VERSION 5.8 ;
BUSBITCHARS "[]" ;
DIVIDERCHAR "/" ;
UNITS
    DATABASE MICRONS 1000 ;
END UNITS

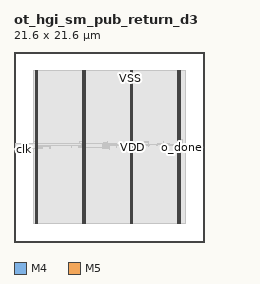
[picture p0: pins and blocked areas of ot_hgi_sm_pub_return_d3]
MACRO ot_hgi_sm_pub_return_d3
  FOREIGN ot_hgi_sm_pub_return_d3 0 0 ;
  CLASS BLOCK ;
  SIZE 21.6 BY 21.6 ;
  PIN clk
    DIRECTION INPUT ;
    USE SIGNAL ;
    PORT
      LAYER M4 ;
        RECT  0 10.512 0.084 10.536 ;
    END
  END clk
  PIN i_done
    DIRECTION INPUT ;
    USE SIGNAL ;
    PORT
      LAYER M4 ;
        RECT  0 10.608 0.084 10.632 ;
    END
  END i_done
  PIN i_fault
    DIRECTION INPUT ;
    USE SIGNAL ;
    PORT
      LAYER M4 ;
        RECT  0 10.704 0.084 10.728 ;
    END
  END i_fault
  PIN o_done
    DIRECTION OUTPUT ;
    USE SIGNAL ;
    PORT
      LAYER M4 ;
        RECT  21.516 10.704 21.6 10.728 ;
    END
  END o_done
  PIN o_fault
    DIRECTION OUTPUT ;
    USE SIGNAL ;
    PORT
      LAYER M4 ;
        RECT  21.516 10.8 21.6 10.824 ;
    END
  END o_fault
  PIN rn
    DIRECTION INPUT ;
    USE SIGNAL ;
    PORT
      LAYER M4 ;
        RECT  0 10.8 0.084 10.824 ;
    END
  END rn
  PIN VDD
    DIRECTION INOUT ;
    USE POWER ;
    PORT
      LAYER M5 ;
        RECT  18.792 2.151 18.912 19.449 ;
        RECT  13.392 2.151 13.512 19.449 ;
        RECT  7.992 2.151 8.112 19.449 ;
        RECT  2.592 2.151 2.712 19.449 ;
    END
  END VDD
  PIN VSS
    DIRECTION INOUT ;
    USE GROUND ;
    PORT
      LAYER M5 ;
        RECT  18.6 2.137 18.72 19.463 ;
        RECT  13.2 2.137 13.32 19.463 ;
        RECT  7.8 2.137 7.92 19.463 ;
        RECT  2.4 2.137 2.52 19.463 ;
    END
  END VSS
  # OT_OBS_CLOSED layer=M5 d_um=1.536 added=0
  OBS
    LAYER RVTN ;
     RECT  2.16 2.16 19.44 2.295 ;
     RECT  2.16 2.565 19.44 2.835 ;
     RECT  2.16 3.105 19.44 3.375 ;
     RECT  2.16 3.645 19.44 3.915 ;
     RECT  2.16 4.185 19.44 4.455 ;
     RECT  2.16 4.725 19.44 4.995 ;
     RECT  2.16 5.265 19.44 5.535 ;
     RECT  2.16 5.805 19.44 6.075 ;
     RECT  2.16 6.345 19.44 6.615 ;
     RECT  2.16 6.885 19.44 7.155 ;
     RECT  2.16 7.425 19.44 7.695 ;
     RECT  2.16 7.965 19.44 8.235 ;
     RECT  2.16 8.505 19.44 8.775 ;
     RECT  2.16 9.045 19.44 9.315 ;
     RECT  2.16 9.585 19.44 9.855 ;
     RECT  2.16 10.125 19.44 10.395 ;
     RECT  2.16 10.665 19.44 10.935 ;
     RECT  2.16 11.205 19.44 11.475 ;
     RECT  2.16 11.745 19.44 12.015 ;
     RECT  2.16 12.285 19.44 12.555 ;
     RECT  2.16 12.825 19.44 13.095 ;
     RECT  2.16 13.365 19.44 13.635 ;
     RECT  2.16 13.905 19.44 14.175 ;
     RECT  2.16 14.445 19.44 14.715 ;
     RECT  2.16 14.985 19.44 15.255 ;
     RECT  2.16 15.525 19.44 15.795 ;
     RECT  2.16 16.065 19.44 16.335 ;
     RECT  2.16 16.605 19.44 16.875 ;
     RECT  2.16 17.145 19.44 17.415 ;
     RECT  2.16 17.685 19.44 17.955 ;
     RECT  2.16 18.225 19.44 18.495 ;
     RECT  2.16 18.765 19.44 19.035 ;
     RECT  2.16 19.305 19.44 19.44 ;
    LAYER RVTP ;
     RECT  2.16 2.295 19.44 2.565 ;
     RECT  2.16 2.835 19.44 3.105 ;
     RECT  2.16 3.375 19.44 3.645 ;
     RECT  2.16 3.915 19.44 4.185 ;
     RECT  2.16 4.455 19.44 4.725 ;
     RECT  2.16 4.995 19.44 5.265 ;
     RECT  2.16 5.535 19.44 5.805 ;
     RECT  2.16 6.075 19.44 6.345 ;
     RECT  2.16 6.615 19.44 6.885 ;
     RECT  2.16 7.155 19.44 7.425 ;
     RECT  2.16 7.695 19.44 7.965 ;
     RECT  2.16 8.235 19.44 8.505 ;
     RECT  2.16 8.775 19.44 9.045 ;
     RECT  2.16 9.315 19.44 9.585 ;
     RECT  2.16 9.855 19.44 10.125 ;
     RECT  2.16 10.395 19.44 10.665 ;
     RECT  2.16 10.935 19.44 11.205 ;
     RECT  2.16 11.475 19.44 11.745 ;
     RECT  2.16 12.015 19.44 12.285 ;
     RECT  2.16 12.555 19.44 12.825 ;
     RECT  2.16 13.095 19.44 13.365 ;
     RECT  2.16 13.635 19.44 13.905 ;
     RECT  2.16 14.175 19.44 14.445 ;
     RECT  2.16 14.715 19.44 14.985 ;
     RECT  2.16 15.255 19.44 15.525 ;
     RECT  2.16 15.795 19.44 16.065 ;
     RECT  2.16 16.335 19.44 16.605 ;
     RECT  2.16 16.875 19.44 17.145 ;
     RECT  2.16 17.415 19.44 17.685 ;
     RECT  2.16 17.955 19.44 18.225 ;
     RECT  2.16 18.495 19.44 18.765 ;
     RECT  2.16 19.035 19.44 19.305 ;
    LAYER M1 ;
     RECT  2.16 2.151 19.44 19.449 ;
    LAYER M2 ;
     RECT  2.16 2.151 19.44 19.449 ;
     RECT  19.44 10.746 20.435 11.124 ;
     RECT  20.435 11.106 20.507 11.124 ;
    LAYER M3 ;
     RECT  2.415 2.143 2.505 2.413 ;
     RECT  7.815 2.143 7.905 2.413 ;
     RECT  13.215 2.143 13.305 2.413 ;
     RECT  18.615 2.143 18.705 2.413 ;
     RECT  18.615 2.413 18.897 10.291 ;
     RECT  18.504 10.291 18.897 10.435 ;
     RECT  2.415 2.413 2.697 10.597 ;
     RECT  4.068 10.597 4.086 10.633 ;
     RECT  10.08 10.597 10.098 10.633 ;
     RECT  10.872 10.471 10.89 10.633 ;
     RECT  2.34 10.597 2.697 10.669 ;
     RECT  2.34 10.669 3.222 10.699 ;
     RECT  18.252 10.435 18.897 10.705 ;
     RECT  7.815 2.413 8.097 10.741 ;
     RECT  10.08 10.633 10.89 10.741 ;
     RECT  20.412 10.699 20.43 10.769 ;
     RECT  2.304 10.699 3.222 10.795 ;
     RECT  2.268 10.795 3.222 10.831 ;
     RECT  4.068 10.633 4.122 10.831 ;
     RECT  7.38 10.741 8.097 10.859 ;
     RECT  6.516 10.741 6.534 10.895 ;
     RECT  9.468 10.741 10.89 10.895 ;
     RECT  2.268 10.831 4.122 10.933 ;
     RECT  13.215 2.413 13.497 10.939 ;
     RECT  15.264 10.831 15.282 10.939 ;
     RECT  2.268 10.933 4.842 10.973 ;
     RECT  5.796 10.939 6.138 10.975 ;
     RECT  10.08 10.895 10.89 10.975 ;
     RECT  11.664 10.741 11.682 10.975 ;
     RECT  12.96 10.939 13.497 10.975 ;
     RECT  16.272 10.939 16.29 10.975 ;
     RECT  7.416 10.859 8.097 11.011 ;
     RECT  12.96 10.975 13.662 11.011 ;
     RECT  15.264 10.939 15.354 11.011 ;
     RECT  17.424 10.741 17.442 11.011 ;
     RECT  18.252 10.705 18.954 11.011 ;
     RECT  16.164 10.975 16.29 11.035 ;
     RECT  17.424 11.011 18.954 11.035 ;
     RECT  14.724 11.011 15.354 11.069 ;
     RECT  12.96 11.011 13.842 11.083 ;
     RECT  2.268 10.973 4.122 11.129 ;
     RECT  5.688 10.975 6.138 11.129 ;
     RECT  10.08 10.975 11.682 11.129 ;
     RECT  12.744 11.083 13.842 11.129 ;
     RECT  16.164 11.035 18.954 11.129 ;
     RECT  20.484 10.795 20.502 11.129 ;
     RECT  5.796 11.129 6.138 11.165 ;
     RECT  7.416 11.011 8.442 11.165 ;
     RECT  10.152 11.129 11.682 11.165 ;
     RECT  12.744 11.129 13.662 11.165 ;
     RECT  16.272 11.129 17.73 11.165 ;
     RECT  2.268 11.129 3.006 11.201 ;
     RECT  4.104 11.129 4.122 11.201 ;
     RECT  5.796 11.165 5.814 11.201 ;
     RECT  16.272 11.165 16.29 11.201 ;
     RECT  17.028 11.165 17.442 11.201 ;
     RECT  11.376 11.165 11.394 11.237 ;
     RECT  18.54 11.129 18.954 11.245 ;
     RECT  10.152 11.165 10.602 11.273 ;
     RECT  12.744 11.165 13.518 11.273 ;
     RECT  12.888 11.273 13.518 11.309 ;
     RECT  14.724 11.069 15.282 11.309 ;
     RECT  7.416 11.165 8.097 11.399 ;
     RECT  10.584 11.273 10.602 11.399 ;
     RECT  13.215 11.309 13.518 11.399 ;
     RECT  14.796 11.309 15.282 11.399 ;
     RECT  17.028 11.201 17.046 11.399 ;
     RECT  2.268 11.201 2.697 11.435 ;
     RECT  15.264 11.399 15.282 11.435 ;
     RECT  18.54 11.245 19.134 11.669 ;
     RECT  18.54 11.669 18.897 11.705 ;
     RECT  2.415 11.435 2.697 19.187 ;
     RECT  7.815 11.399 8.097 19.187 ;
     RECT  13.215 11.399 13.497 19.187 ;
     RECT  18.615 11.705 18.897 19.187 ;
     RECT  2.415 19.187 2.505 19.457 ;
     RECT  7.815 19.187 7.905 19.457 ;
     RECT  13.215 19.187 13.305 19.457 ;
     RECT  18.615 19.187 18.705 19.457 ;
    LAYER M4 ;
     RECT  0.06 10.512 0.133 10.824 ;
     RECT  0.133 10.512 0.179 11.208 ;
     RECT  0.179 10.608 2.408 11.208 ;
     RECT  2.408 2.148 2.512 19.452 ;
     RECT  2.512 2.418 2.704 19.182 ;
     RECT  2.704 10.944 7.657 11.208 ;
     RECT  7.657 10.848 7.669 11.208 ;
     RECT  7.669 10.704 7.808 11.208 ;
     RECT  7.808 2.148 7.912 19.452 ;
     RECT  7.912 2.418 8.104 19.182 ;
     RECT  8.104 10.704 10.109 11.208 ;
     RECT  10.109 10.896 10.181 11.208 ;
     RECT  10.181 10.896 10.217 11.112 ;
     RECT  10.217 10.944 13.208 11.112 ;
     RECT  13.208 2.148 13.312 19.452 ;
     RECT  13.312 2.418 13.504 19.182 ;
     RECT  13.504 10.944 15.325 10.968 ;
     RECT  15.325 10.944 15.365 11.064 ;
     RECT  15.365 11.04 16.913 11.064 ;
     RECT  18.608 2.148 18.712 19.452 ;
     RECT  18.712 2.418 18.904 19.182 ;
     RECT  20.401 10.704 20.473 10.728 ;
     RECT  20.473 10.704 21.564 10.824 ;
    LAYER M5 ;
     RECT  2.4 2.137 2.52 2.151 ;
     RECT  7.8 2.137 7.92 2.151 ;
     RECT  13.2 2.137 13.32 2.151 ;
     RECT  18.6 2.137 18.72 2.151 ;
     RECT  7.8 2.151 8.112 10.693 ;
     RECT  7.68 10.693 8.112 10.883 ;
     RECT  0.144 10.501 0.168 11.219 ;
     RECT  2.4 2.151 2.712 19.449 ;
     RECT  7.8 10.883 8.112 19.449 ;
     RECT  13.2 2.151 13.512 19.449 ;
     RECT  18.6 2.151 18.912 19.449 ;
     RECT  2.4 19.449 2.52 19.463 ;
     RECT  7.8 19.449 7.92 19.463 ;
     RECT  13.2 19.449 13.32 19.463 ;
     RECT  18.6 19.449 18.72 19.463 ;
  END
END ot_hgi_sm_pub_return_d3
END LIBRARY
